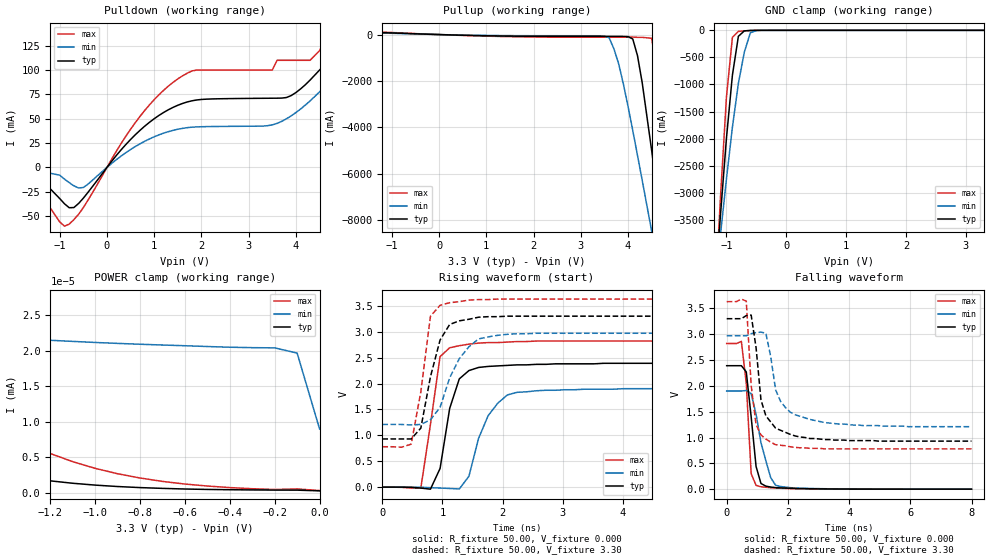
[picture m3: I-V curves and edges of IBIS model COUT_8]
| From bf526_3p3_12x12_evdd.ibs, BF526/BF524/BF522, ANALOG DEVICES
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|   Model prw0408swcdg_25
[Model]   COUT_8
Model_type   I/O
Polarity   Non-Inverting
Enable   Active-Low
Vinl =   0.40V
Vinh =   2.40V
Vmeas =   1.20V
Cref =  50.00pF
Rref =   1.00M
Vref =  0.000V
C_comp   4.77pF   4.29pF   5.25pF
[Temperature Range]   25.00   0.12k   -40.00
[Voltage Range]   3.30V   2.97V   3.63V
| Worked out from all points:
|   slope of the pulldown table from 0 to 0.495 V, typ, clamps not added: 17.4 ohm
|   slope of the pullup table from 0 to 0.495 V, typ, clamps not added: 17.2 ohm
|   GND clamp passes 1 mA (typ) near -0.53 V on its own axis
|   POWER clamp passes 1 mA (typ) near -3.01 V on its own axis
|   rising waveform, R_fixture 50.00, V_fixture 0.000: 20-80 % time 254ps typ, 376ps min, 212ps max; typ from 0 V to 2.39 V
|   rising waveform, R_fixture 50.00, V_fixture 3.30: 20-80 % time 274ps typ, 410ps min, 211ps max; typ from 0.93 V to 3.3 V
|   falling waveform, R_fixture 50.00, V_fixture 0.000: 20-80 % time 248ps typ, 430ps min, 177ps max; typ from 2.39 V to 0 V
|   falling waveform, R_fixture 50.00, V_fixture 3.30: 20-80 % time 363ps typ, 532ps min, 242ps max; typ from 3.3 V to 0.93 V
[Pulldown]
| voltage   I(typ)   I(min)   I(max)
-3.3V     0A         0A         0A
-1.7V     0A         0A         -10mA
-900mV    -37.3mA    -12mA      -60.3mA
-500mV    -31.56mA   -20.64mA   -41.25mA
700mV     38.11mA    24.26mA    52.44mA
1.7V      67.22mA    40.81mA    96.76mA
3.9V      73.78mA    52.99mA    110mA
4.3V      89.73mA    68.32mA    110mA
5.1V      140mA      110mA      170mA
5.5V      170mA      59.23mA    210mA
6.1V      130mA      60.45mA    270mA
6.6V      890mA      68.62mA    3.72A
[Pullup]
| voltage   I(typ)   I(min)   I(max)
-3.3V     29.2mA     8.62mA     61mA
-2.5V     150mA      14.34mA    190mA
3.6V      -78.87mA   -140mA     -110mA
3.8V      -79.53mA   -1.25A     -110mA
4.1V      -190mA     -4.14A     -110mA
4.2V      -910mA     -5.21A     -120mA
4.3V      -2.08A     -6.29A     -120mA
4.5V      -5A        -8.48A     -160mA
4.7V      -8.09A     -10.68A    -2.62A
4.9V      -11.24A    -12.9A     -6.81A
5.1V      -14.4A     -15.12A    -11.2A
6.6V      -38.32A    -31.88A    -44.78A
[GND_clamp]
| voltage   I(typ)   I(min)   I(max)
-3.3V     -38.23A    -28.13A    -52.07A
-1.2V     -4.92A     -4.84A     -5.19A
-1.1V     -3.42A     -3.78A     -3.1A
-1V       -2A        -2.75A     -1.24A
-900mV    -830mA     -1.79A     -130mA
-800mV    -110mA     -980mA     -19.35mA
-700mV    -10.17mA   -400mA     -9.85mA
-600mV    -2.61mA    -45.18mA   -3.52mA
-500mV    -460uA     -4.57mA    -550uA
3.3V      270pA      20.45nA    210pA
[POWER_clamp]
| voltage   I(typ)   I(min)   I(max)
-3.3V     770mA      230nA      7.85A
-2.6V     27.1nA     32.41nA    9.27mA
-2.3V     16.42nA    27.61nA    47.25nA
-2V       9.44nA     24.65nA    26.73nA
-1.7V     5.12nA     22.9nA     15.66nA
-1.5V     3.3nA      22.17nA    10.58nA
-1.3V     2.1nA      21.67nA    6.92nA
-1.1V     1.34nA     21.32nA    4.38nA
-800mV    730pA      20.92nA    2.08nA
-200mV    380pA      20.41nA    460pA
-100mV    370pA      19.67nA    540pA
0V        270pA      8.98nA     310pA
[Ramp]
| variable   typ   min   max
dV/dt_r   1.43/0.22n   1.14/0.32n   1.69/0.15n
dV/dt_f   1.42/0.31n   1.06/0.48n   1.71/0.20n
R_load = 50.00
[Rising Waveform]
R_fixture = 50.00
V_fixture = 0.000
V_fixture_min = 0.000
V_fixture_max = 0.000
L_fixture = 0.000H
C_fixture = 0.000F
| time   V(typ)   V(min)   V(max)
0s        0V         0V         0V
640ps     -17.92mV   -2.16mV    -17.85mV
800ps     -39.03mV   -10.67mV   1.21V
960ps     360mV      -17.53mV   2.52V
1.12ns    1.52V      -25.78mV   2.69V
1.28ns    2.09V      -34.99mV   2.73V
1.44ns    2.25V      210mV      2.76V
1.76ns    2.33V      1.38V      2.79V
2.24ns    2.36V      1.83V      2.81V
8ns       2.39V      1.9V       2.82V
[Rising Waveform]
R_fixture = 50.00
V_fixture = 3.30
V_fixture_min = 2.97
V_fixture_max = 3.63
L_fixture = 0.000H
C_fixture = 0.000F
| time   V(typ)   V(min)   V(max)
0s        930mV      1.21V      780mV
480ps     930mV      1.2V       830mV
640ps     1.14V      1.21V      1.84V
800ps     2.13V      1.3V       3.3V
960ps     2.84V      1.54V      3.51V
1.12ns    3.14V      2.11V      3.56V
1.28ns    3.21V      2.48V      3.58V
1.6ns     3.28V      2.86V      3.62V
1.76ns    3.29V      2.9V       3.62V
8ns       3.3V       2.97V      3.63V
[Falling Waveform]
R_fixture = 50.00
V_fixture = 0.000
V_fixture_min = 0.000
V_fixture_max = 0.000
L_fixture = 0.000H
C_fixture = 0.000F
| time   V(typ)   V(min)   V(max)
0s        2.39V      1.9V       2.82V
480ps     2.39V      1.9V       2.86V
640ps     2.27V      1.91V      2.05V
800ps     1.4V       1.85V      300mV
960ps     440mV      1.45V      74.04mV
1.12ns    110mV      900mV      46.09mV
1.44ns    40.99mV    220mV      28.16mV
1.6ns     29.84mV    75.56mV    21.47mV
2.72ns    7.89mV     13.37mV    4.34mV
8ns       10.85uV    120uV      15.04uV
[Falling Waveform]
R_fixture = 50.00
V_fixture = 3.30
V_fixture_min = 2.97
V_fixture_max = 3.63
L_fixture = 0.000H
C_fixture = 0.000F
| time   V(typ)   V(min)   V(max)
0s        3.3V       2.97V      3.63V
640ps     3.36V      2.97V      3.64V
800ps     3.37V      3.01V      2.01V
960ps     2.74V      3.03V      1.25V
1.12ns    1.73V      3.04V      1.05V
1.28ns    1.42V      3.02V      970mV
1.44ns    1.3V       2.56V      910mV
1.6ns     1.18V      1.92V      860mV
2.24ns    1.03V      1.44V      810mV
8ns       930mV      1.21V      780mV
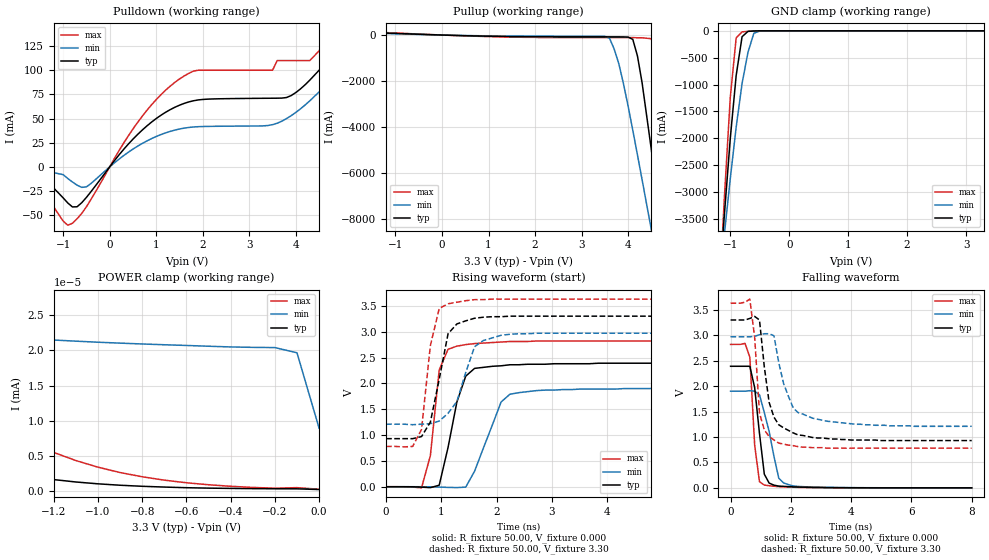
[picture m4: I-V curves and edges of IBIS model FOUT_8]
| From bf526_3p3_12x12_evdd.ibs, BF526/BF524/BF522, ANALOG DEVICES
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|   Model prw0408swcdg_3v_25
[Model]   FOUT_8
Model_type   I/O
Polarity   Non-Inverting
Enable   Active-Low
Vinl =   0.40V
Vinh =   2.40V
Vmeas =   1.20V
Cref =  50.00pF
Rref =   1.00M
Vref =  0.000V
C_comp   5.08pF   4.58pF   5.59pF
[Temperature Range]   25.00   0.12k   -40.00
[Voltage Range]   3.30V   2.97V   3.63V
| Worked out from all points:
|   slope of the pulldown table from 0 to 0.495 V, typ, clamps not added: 17.4 ohm
|   slope of the pullup table from 0 to 0.495 V, typ, clamps not added: 17.2 ohm
|   GND clamp passes 1 mA (typ) near -0.53 V on its own axis
|   POWER clamp passes 1 mA (typ) near -3.01 V on its own axis
|   rising waveform, R_fixture 50.00, V_fixture 0.000: 20-80 % time 309ps typ, 409ps min, 169ps max; typ from 0 V to 2.39 V
|   rising waveform, R_fixture 50.00, V_fixture 3.30: 20-80 % time 266ps typ, 352ps min, 210ps max; typ from 0.93 V to 3.3 V
|   falling waveform, R_fixture 50.00, V_fixture 0.000: 20-80 % time 268ps typ, 428ps min, 192ps max; typ from 2.39 V to 0 V
|   falling waveform, R_fixture 50.00, V_fixture 3.30: 20-80 % time 390ps typ, 542ps min, 240ps max; typ from 3.3 V to 0.93 V
[Pulldown]
| voltage   I(typ)   I(min)   I(max)
-3.3V     0A         0A         0A
-1.7V     0A         0A         -10mA
-900mV    -37.3mA    -12mA      -60.3mA
-500mV    -31.56mA   -20.64mA   -41.25mA
700mV     38.11mA    24.26mA    52.44mA
1.7V      67.22mA    40.81mA    96.76mA
3.9V      73.78mA    52.99mA    110mA
4.3V      89.73mA    68.32mA    110mA
5.1V      140mA      110mA      170mA
5.5V      170mA      59.23mA    210mA
6.1V      130mA      60.45mA    270mA
6.6V      890mA      68.62mA    3.72A
[Pullup]
| voltage   I(typ)   I(min)   I(max)
-3.3V     29.2mA     8.62mA     61mA
-2.5V     150mA      14.34mA    190mA
3.6V      -78.87mA   -140mA     -110mA
3.8V      -79.53mA   -1.25A     -110mA
4.1V      -190mA     -4.14A     -110mA
4.2V      -910mA     -5.21A     -120mA
4.3V      -2.08A     -6.29A     -120mA
4.5V      -5A        -8.48A     -160mA
4.7V      -8.09A     -10.68A    -2.62A
4.9V      -11.24A    -12.9A     -6.81A
5.1V      -14.4A     -15.12A    -11.2A
6.6V      -38.32A    -31.88A    -44.78A
[GND_clamp]
| voltage   I(typ)   I(min)   I(max)
-3.3V     -38.23A    -28.13A    -52.07A
-1.2V     -4.92A     -4.84A     -5.19A
-1.1V     -3.42A     -3.78A     -3.1A
-1V       -2A        -2.75A     -1.24A
-900mV    -830mA     -1.79A     -130mA
-800mV    -110mA     -980mA     -19.35mA
-700mV    -10.17mA   -400mA     -9.85mA
-600mV    -2.61mA    -45.18mA   -3.52mA
-500mV    -460uA     -4.57mA    -550uA
3.3V      270pA      20.45nA    210pA
[POWER_clamp]
| voltage   I(typ)   I(min)   I(max)
-3.3V     770mA      230nA      7.85A
-2.6V     27.1nA     32.41nA    9.27mA
-2.3V     16.42nA    27.61nA    47.25nA
-2V       9.44nA     24.65nA    26.73nA
-1.7V     5.12nA     22.9nA     15.66nA
-1.5V     3.3nA      22.17nA    10.58nA
-1.3V     2.1nA      21.67nA    6.92nA
-1.1V     1.34nA     21.32nA    4.38nA
-800mV    730pA      20.92nA    2.08nA
-200mV    380pA      20.41nA    460pA
-100mV    370pA      19.67nA    540pA
0V        270pA      8.98nA     310pA
[Ramp]
| variable   typ   min   max
dV/dt_r   1.43/0.21n   1.14/0.33n   1.69/0.16n
dV/dt_f   1.42/0.31n   1.06/0.49n   1.71/0.20n
R_load = 50.00
[Rising Waveform]
R_fixture = 50.00
V_fixture = 0.000
V_fixture_min = 0.000
V_fixture_max = 0.000
L_fixture = 0.000H
C_fixture = 0.000F
| time   V(typ)   V(min)   V(max)
0s        0V         0V         0V
640ps     -8.17mV    -460uV     -21.94mV
800ps     -17.89mV   -3.01mV    600mV
960ps     29.33mV    -7.23mV    2.26V
1.28ns    1.64V      -16.71mV   2.72V
1.44ns    2.14V      -7.59mV    2.75V
1.6ns     2.29V      300mV      2.77V
2.08ns    2.34V      1.64V      2.8V
2.24ns    2.36V      1.79V      2.81V
8ns       2.39V      1.9V       2.82V
[Rising Waveform]
R_fixture = 50.00
V_fixture = 3.30
V_fixture_min = 2.97
V_fixture_max = 3.63
L_fixture = 0.000H
C_fixture = 0.000F
| time   V(typ)   V(min)   V(max)
0s        930mV      1.21V      780mV
480ps     930mV      1.2V       780mV
640ps     970mV      1.21V      1.11V
800ps     1.25V      1.22V      2.73V
960ps     2.08V      1.27V      3.45V
1.12ns    2.96V      1.42V      3.54V
1.28ns    3.15V      1.65V      3.57V
1.6ns     3.26V      2.71V      3.62V
2.08ns    3.29V      2.93V      3.63V
8ns       3.3V       2.97V      3.63V
[Falling Waveform]
R_fixture = 50.00
V_fixture = 0.000
V_fixture_min = 0.000
V_fixture_max = 0.000
L_fixture = 0.000H
C_fixture = 0.000F
| time   V(typ)   V(min)   V(max)
0s        2.39V      1.9V       2.82V
480ps     2.39V      1.9V       2.84V
640ps     2.39V      1.91V      2.57V
800ps     1.97V      1.9V       840mV
960ps     1.07V      1.83V      120mV
1.12ns    270mV      1.48V      55.04mV
1.28ns    93.48mV    1.11V      41.63mV
1.6ns     35mV       190mV      23.4mV
1.76ns    29.42mV    96.68mV    20.12mV
8ns       2.74uV     120uV      -2.98uV
[Falling Waveform]
R_fixture = 50.00
V_fixture = 3.30
V_fixture_min = 2.97
V_fixture_max = 3.63
L_fixture = 0.000H
C_fixture = 0.000F
| time   V(typ)   V(min)   V(max)
0s        3.3V       2.97V      3.63V
640ps     3.33V      2.97V      3.71V
800ps     3.37V      2.98V      2.96V
960ps     3.3V       3.01V      1.47V
1.28ns    1.68V      3.03V      1.01V
1.44ns    1.39V      2.99V      940mV
1.6ns     1.24V      2.46V      880mV
2.08ns    1.08V      1.57V      830mV
2.72ns    990mV      1.37V      790mV
8ns       930mV      1.21V      780mV
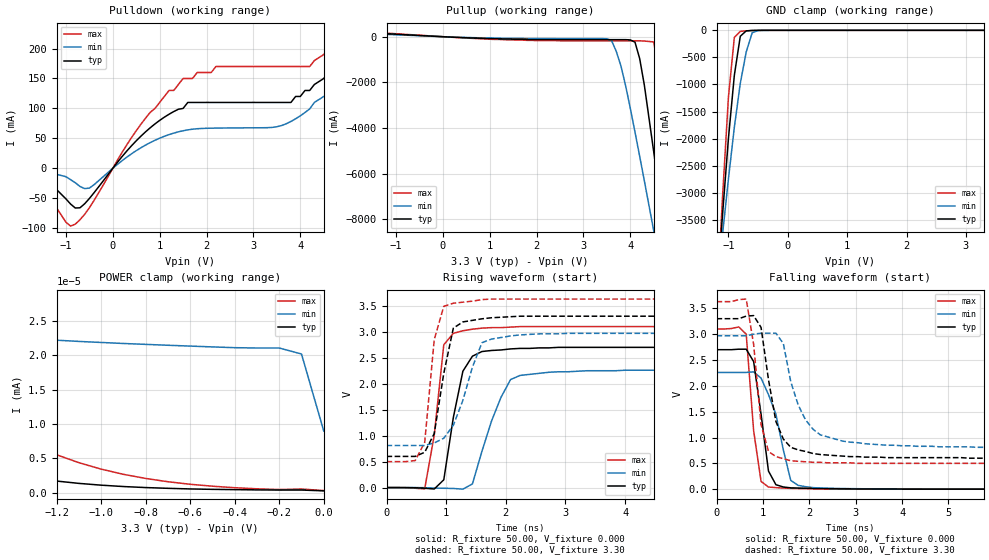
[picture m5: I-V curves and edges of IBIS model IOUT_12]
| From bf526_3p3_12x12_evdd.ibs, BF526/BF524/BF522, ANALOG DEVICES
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|   Model prw0812swcdg_25
[Model]   IOUT_12
Model_type   I/O
Polarity   Non-Inverting
Enable   Active-Low
Vinl =   0.40V
Vinh =   2.40V
Vmeas =   1.20V
Cref =  50.00pF
Rref =   1.00M
Vref =  0.000V
C_comp   4.62pF   4.16pF   5.08pF
[Temperature Range]   25.00   0.12k   -40.00
[Voltage Range]   3.30V   2.97V   3.63V
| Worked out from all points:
|   slope of the pulldown table from 0 to 0.495 V, typ, clamps not added: 10.9 ohm
|   slope of the pullup table from 0 to 0.495 V, typ, clamps not added: 10.8 ohm
|   GND clamp passes 1 mA (typ) near -0.53 V on its own axis
|   POWER clamp passes 1 mA (typ) near -3.01 V on its own axis
|   rising waveform, R_fixture 50.00, V_fixture 0.000: 20-80 % time 254ps typ, 415ps min, 195ps max; typ from 0 V to 2.7 V
|   rising waveform, R_fixture 50.00, V_fixture 3.30: 20-80 % time 249ps typ, 380ps min, 178ps max; typ from 0.6 V to 3.3 V
|   falling waveform, R_fixture 50.00, V_fixture 0.000: 20-80 % time 244ps typ, 394ps min, 199ps max; typ from 2.7 V to 0 V
|   falling waveform, R_fixture 50.00, V_fixture 3.30: 20-80 % time 341ps typ, 506ps min, 235ps max; typ from 3.3 V to 0.6 V
[Pulldown]
| voltage   I(typ)   I(min)   I(max)
-3.3V     0A         0A         0A
-2.1V     0A         0A         0A
-900mV    -59.7mA    -19mA      -96.5mA
-500mV    -50.5mA    -33.03mA   -66mA
600mV     53.68mA    34.3mA     73.6mA
1.5V      100mA      62.7mA     150mA
3.8V      110mA      78.23mA    170mA
5.1V      210mA      170mA      260mA
5.5V      260mA      93.31mA    320mA
5.9V      300mA      93.01mA    380mA
6.1V      200mA      95.25mA    410mA
6.6V      960mA      110mA      3.87A
[Pullup]
| voltage   I(typ)   I(min)   I(max)
-3.3V     42mA       12.24mA    86mA
-2.7V     200mA      16.46mA    290mA
3.6V      -130mA     -170mA     -180mA
3.8V      -130mA     -1.28A     -180mA
4.1V      -240mA     -4.18A     -180mA
4.2V      -960mA     -5.24A     -180mA
4.3V      -2.13A     -6.32A     -190mA
4.5V      -5.05A     -8.51A     -230mA
4.7V      -8.14A     -10.71A    -2.69A
4.9V      -11.28A    -12.93A    -6.88A
5.1V      -14.45A    -15.15A    -11.27A
6.6V      -38.37A    -31.91A    -44.86A
[GND_clamp]
| voltage   I(typ)   I(min)   I(max)
-3.3V     -38.23A    -28.13A    -52.07A
-1.2V     -4.92A     -4.84A     -5.19A
-1.1V     -3.42A     -3.78A     -3.1A
-1V       -2A        -2.75A     -1.24A
-900mV    -830mA     -1.79A     -130mA
-800mV    -110mA     -980mA     -19.35mA
-700mV    -10.17mA   -400mA     -9.85mA
-600mV    -2.61mA    -45.18mA   -3.52mA
-500mV    -460uA     -4.57mA    -550uA
3.3V      270pA      21.08nA    210pA
[POWER_clamp]
| voltage   I(typ)   I(min)   I(max)
-3.3V     770mA      230nA      7.85A
-2.7V     34.08nA    35.51nA    340mA
-2.6V     27.13nA    33.37nA    9.27mA
-2.4V     19.53nA    29.9nA     610nA
-2.1V     11.45nA    26.35nA    31.53nA
-2V       9.46nA     25.51nA    26.73nA
-1.6V     4.14nA     23.31nA    12.92nA
-1.3V     2.12nA     22.43nA    6.92nA
-800mV    750pA      21.61nA    2.08nA
-200mV    390pA      21.08nA    460pA
-100mV    390pA      20.21nA    540pA
0V        270pA      8.99nA     310pA
[Ramp]
| variable   typ   min   max
dV/dt_r   1.62/0.20n   1.36/0.32n   1.86/0.14n
dV/dt_f   1.62/0.27n   1.30/0.43n   1.88/0.20n
R_load = 50.00
[Rising Waveform]
R_fixture = 50.00
V_fixture = 0.000
V_fixture_min = 0.000
V_fixture_max = 0.000
L_fixture = 0.000H
C_fixture = 0.000F
| time   V(typ)   V(min)   V(max)
0s        0V         0V         0V
640ps     -12.99mV   -2.01mV    -25.12mV
800ps     -27.4mV    -9.06mV    1.01V
960ps     150mV      -13.2mV    2.75V
1.12ns    1.35V      -17.31mV   2.97V
1.28ns    2.24V      -30.54mV   3.02V
1.44ns    2.53V      70.07mV    3.05V
1.92ns    2.65V      1.74V      3.08V
2.24ns    2.68V      2.16V      3.1V
8ns       2.7V       2.26V      3.1V
[Rising Waveform]
R_fixture = 50.00
V_fixture = 3.30
V_fixture_min = 2.97
V_fixture_max = 3.63
L_fixture = 0.000H
C_fixture = 0.000F
| time   V(typ)   V(min)   V(max)
0s        600mV      810mV      500mV
480ps     600mV      810mV      520mV
640ps     680mV      810mV      870mV
800ps     1.04V      860mV      2.85V
960ps     2.2V       950mV      3.49V
1.12ns    3.07V      1.2V       3.55V
1.6ns     3.25V      2.79V      3.62V
1.76ns    3.27V      2.86V      3.63V
3.04ns    3.3V       2.97V      3.63V
8ns       3.3V       2.97V      3.63V
[Falling Waveform]
R_fixture = 50.00
V_fixture = 0.000
V_fixture_min = 0.000
V_fixture_max = 0.000
L_fixture = 0.000H
C_fixture = 0.000F
| time   V(typ)   V(min)   V(max)
0s        2.7V       2.26V      3.1V
480ps     2.71V      2.26V      3.14V
640ps     2.71V      2.26V      3V
800ps     2.47V      2.27V      1.13V
960ps     1.45V      2.15V      150mV
1.12ns    350mV      1.83V      40.93mV
1.28ns    86.15mV    1.45V      29.38mV
1.6ns     25.64mV    170mV      15.47mV
1.76ns    21.11mV    73.27mV    13.14mV
8ns       18.07uV    64.3uV     6.9uV
[Falling Waveform]
R_fixture = 50.00
V_fixture = 3.30
V_fixture_min = 2.97
V_fixture_max = 3.63
L_fixture = 0.000H
C_fixture = 0.000F
| time   V(typ)   V(min)   V(max)
0s        3.3V       2.97V      3.63V
640ps     3.35V      2.97V      3.68V
800ps     3.36V      3V         2.8V
960ps     3.13V      3.02V      1.25V
1.12ns    2.12V      3.02V      730mV
1.28ns    1.31V      3.02V      630mV
1.44ns    970mV      2.82V      590mV
1.76ns    760mV      1.63V      540mV
2.24ns    670mV      1.05V      520mV
8ns       600mV      810mV      500mV
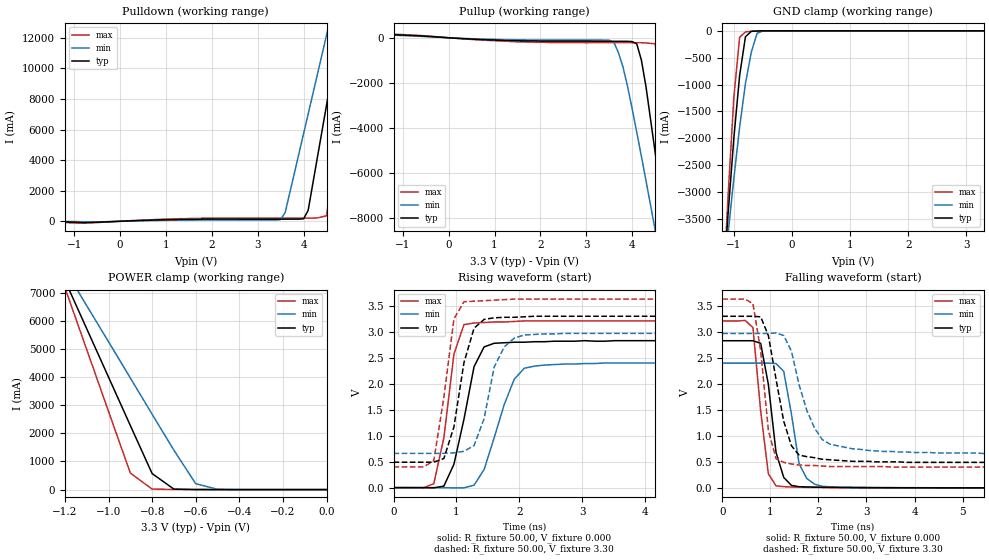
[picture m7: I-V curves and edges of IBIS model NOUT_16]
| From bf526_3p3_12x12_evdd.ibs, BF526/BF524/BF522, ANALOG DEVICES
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|   Model prw1216hcdg_25
[Model]   NOUT_16
Model_type   I/O
Polarity   Non-Inverting
Enable   Active-Low
Vinl =   0.40V
Vinh =   2.40V
Vmeas =   1.20V
Cref =  50.00pF
Rref =   1.00M
Vref =  0.000V
C_comp   4.70pF   4.23pF   5.17pF
[Temperature Range]   25.00   0.12k   -40.00
[Voltage Range]   3.30V   2.97V   3.63V
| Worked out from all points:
|   slope of the pulldown table from 0 to 0.495 V, typ, clamps not added: 8.7 ohm
|   slope of the pullup table from 0 to 0.495 V, typ, clamps not added: 8.43 ohm
|   GND clamp passes 1 mA (typ) near -0.52 V on its own axis
|   POWER clamp passes 1 mA (typ) near -0.53 V on its own axis
|   rising waveform, R_fixture 50.00, V_fixture 0.000: 20-80 % time 288ps typ, 390ps min, 217ps max; typ from 0 V to 2.83 V
|   rising waveform, R_fixture 50.00, V_fixture 3.30: 20-80 % time 270ps typ, 301ps min, 223ps max; typ from 0.49 V to 3.3 V
|   falling waveform, R_fixture 50.00, V_fixture 0.000: 20-80 % time 253ps typ, 254ps min, 220ps max; typ from 2.83 V to 0 V
|   falling waveform, R_fixture 50.00, V_fixture 3.30: 20-80 % time 361ps typ, 470ps min, 240ps max; typ from 3.3 V to 0.49 V
[Pulldown]
| voltage   I(typ)   I(min)   I(max)
-3.3V     0A         0A         -10mA
-800mV    -82.8mA    -31.1mA    -120mA
1.3V      120mA      73.45mA    170mA
3.5V      140mA      110mA      210mA
3.6V      140mA      580mA      210mA
4V        160mA      5.73A      210mA
4.1V      710mA      7.01A      210mA
4.5V      7.59A      12.17A     360mA
4.7V      11.02A     14.75A     4.54A
4.9V      14.47A     17.33A     8.94A
5.1V      17.91A     19.91A     13.34A
6.6V      44.58A     39.34A     49.85A
[Pullup]
| voltage   I(typ)   I(min)   I(max)
-3.3V     300mA      300mA      320mA
1.5V      -130mA     -92.18mA   -180mA
3.6V      -160mA     -200mA     -220mA
3.8V      -160mA     -1.3A      -220mA
4.1V      -270mA     -4.2A      -220mA
4.2V      -990mA     -5.26A     -220mA
4.3V      -2.16A     -6.34A     -230mA
4.5V      -5.08A     -8.53A     -270mA
4.7V      -8.17A     -10.73A    -2.73A
4.9V      -11.31A    -12.95A    -6.92A
5.1V      -14.48A    -15.17A    -11.31A
6.6V      -38.4A     -31.93A    -44.89A
[GND_clamp]
| voltage   I(typ)   I(min)   I(max)
-3.3V     -38.23A    -28.13A    -52.07A
-1.2V     -4.92A     -4.84A     -5.19A
-1.1V     -3.42A     -3.78A     -3.1A
-1V       -2A        -2.75A     -1.24A
-900mV    -830mA     -1.79A     -120mA
-800mV    -110mA     -980mA     -19.29mA
-700mV    -10.14mA   -400mA     -9.82mA
-600mV    -2.6mA     -45.13mA   -3.51mA
-500mV    -470uA     -4.54mA    -560uA
3.3V      250pA      110uA      -8.75uA
[POWER_clamp]
| voltage   I(typ)   I(min)   I(max)
-3.3V     44.38A     34.94A     61.27A
-1.2V     7.44A      7.83A      7.18A
-1.1V     5.72A      6.54A      4.98A
-900mV    2.28A      3.97A      590mA
-800mV    570mA      2.68A      17.01mA
-700mV    17.04mA    1.4A       7.1mA
-600mV    2.37mA     210mA      2.78mA
-500mV    470uA      11.87mA    550uA
0V        250pA      8.85nA     290pA
[Ramp]
| variable   typ   min   max
dV/dt_r   1.70/0.24n   1.44/0.33n   1.93/0.20n
dV/dt_f   1.69/0.29n   1.39/0.41n   1.94/0.21n
R_load = 50.00
[Rising Waveform]
R_fixture = 50.00
V_fixture = 0.000
V_fixture_min = 0.000
V_fixture_max = 0.000
L_fixture = 0.000H
C_fixture = 0.000F
| time   V(typ)   V(min)   V(max)
0s        0V         0V         0V
640ps     -3.92mV    -170uV     76.34mV
800ps     29.17mV    -1.52mV    960mV
960ps     450mV      -4.29mV    2.57V
1.12ns    1.32V      -3.14mV    3.14V
1.28ns    2.33V      46.2mV     3.17V
1.44ns    2.71V      350mV      3.18V
1.92ns    2.8V       2.09V      3.2V
2.08ns    2.8V       2.3V       3.21V
8ns       2.83V      2.4V       3.21V
[Rising Waveform]
R_fixture = 50.00
V_fixture = 3.30
V_fixture_min = 2.97
V_fixture_max = 3.63
L_fixture = 0.000H
C_fixture = 0.000F
| time   V(typ)   V(min)   V(max)
0s        490mV      660mV      400mV
640ps     490mV      660mV      520mV
800ps     560mV      660mV      1.74V
960ps     1.17V      670mV      3.25V
1.12ns    2.41V      700mV      3.58V
1.28ns    3.07V      810mV      3.59V
1.44ns    3.24V      1.33V      3.6V
1.6ns     3.27V      2.32V      3.61V
2.08ns    3.29V      2.94V      3.63V
8ns       3.3V       2.97V      3.63V
[Falling Waveform]
R_fixture = 50.00
V_fixture = 0.000
V_fixture_min = 0.000
V_fixture_max = 0.000
L_fixture = 0.000H
C_fixture = 0.000F
| time   V(typ)   V(min)   V(max)
0s        2.83V      2.4V       3.21V
480ps     2.83V      2.4V       3.22V
640ps     2.83V      2.4V       3.08V
800ps     2.78V      2.4V       1.48V
960ps     1.99V      2.4V       270mV
1.12ns    680mV      2.39V      38.62mV
1.28ns    200mV      2.24V      22.89mV
1.6ns     22.21mV    460mV      12.46mV
1.92ns    14.33mV    71.43mV    8.49mV
8ns       39.64uV    120uV      16.62uV
[Falling Waveform]
R_fixture = 50.00
V_fixture = 3.30
V_fixture_min = 2.97
V_fixture_max = 3.63
L_fixture = 0.000H
C_fixture = 0.000F
| time   V(typ)   V(min)   V(max)
0s        3.3V       2.97V      3.63V
640ps     3.3V       2.97V      3.54V
800ps     3.29V      2.97V      2.64V
960ps     2.93V      2.97V      1.11V
1.12ns    2.09V      2.98V      560mV
1.28ns    1.28V      2.93V      490mV
1.6ns     630mV      1.98V      440mV
1.92ns    580mV      1.15V      430mV
2.24ns    540mV      840mV      410mV
8ns       490mV      660mV      400mV
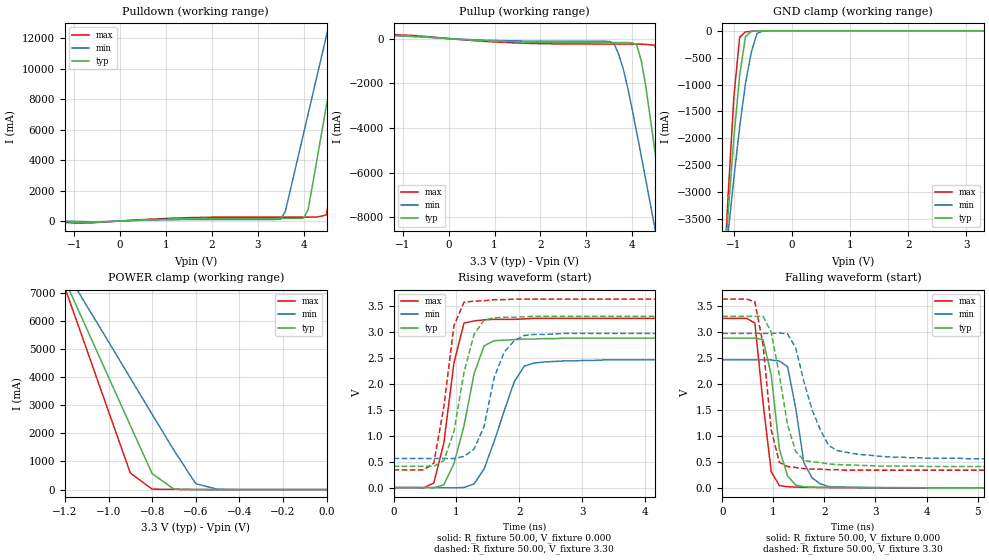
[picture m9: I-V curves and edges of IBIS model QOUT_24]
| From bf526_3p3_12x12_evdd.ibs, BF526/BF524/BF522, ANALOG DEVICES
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|   Model prw1624cdg_25
[Model]   QOUT_24
Model_type   I/O
Polarity   Non-Inverting
Enable   Active-Low
Vinl =   0.40V
Vinh =   2.40V
Vmeas =   1.20V
Cref =  50.00pF
Rref =   1.00M
Vref =  0.000V
C_comp   4.55pF   4.10pF   5.01pF
[Temperature Range]   25.00   0.12k   -40.00
[Voltage Range]   3.30V   2.97V   3.63V
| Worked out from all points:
|   slope of the pulldown table from 0 to 0.495 V, typ, clamps not added: 7.25 ohm
|   slope of the pullup table from 0 to 0.495 V, typ, clamps not added: 7.49 ohm
|   GND clamp passes 1 mA (typ) near -0.53 V on its own axis
|   POWER clamp passes 1 mA (typ) near -0.53 V on its own axis
|   rising waveform, R_fixture 50.00, V_fixture 0.000: 20-80 % time 328ps typ, 420ps min, 246ps max; typ from 0 V to 2.88 V
|   rising waveform, R_fixture 50.00, V_fixture 3.30: 20-80 % time 296ps typ, 330ps min, 227ps max; typ from 0.41 V to 3.3 V
|   falling waveform, R_fixture 50.00, V_fixture 0.000: 20-80 % time 243ps typ, 246ps min, 220ps max; typ from 2.88 V to 0 V
|   falling waveform, R_fixture 50.00, V_fixture 3.30: 20-80 % time 338ps typ, 472ps min, 232ps max; typ from 3.3 V to 0.41 V
[Pulldown]
| voltage   I(typ)   I(min)   I(max)
-3.3V     0A         0A         -10mA
-800mV    -99.3mA    -37.1mA    -140mA
1.6V      160mA      96.25mA    230mA
3.5V      170mA      130mA      250mA
3.6V      170mA      600mA      250mA
4V        190mA      5.74A      250mA
4.1V      740mA      7.03A      250mA
4.5V      7.61A      12.18A     400mA
4.7V      11.05A     14.76A     4.58A
4.9V      14.5A      17.34A     8.98A
5.1V      17.94A     19.93A     13.38A
6.6V      44.61A     39.37A     49.91A
[Pullup]
| voltage   I(typ)   I(min)   I(max)
-3.3V     340mA      340mA      360mA
1V        -120mA     -83mA      -150mA
3.6V      -180mA     -210mA     -250mA
3.8V      -180mA     -1.31A     -250mA
4.1V      -290mA     -4.21A     -250mA
4.2V      -1.01A     -5.28A     -250mA
4.3V      -2.18A     -6.36A     -260mA
4.5V      -5.1A      -8.54A     -300mA
4.7V      -8.19A     -10.75A    -2.76A
4.9V      -11.33A    -12.96A    -6.95A
5.1V      -14.5A     -15.19A    -11.34A
6.6V      -38.42A    -31.95A    -44.92A
[GND_clamp]
| voltage   I(typ)   I(min)   I(max)
-3.3V     -38.23A    -28.13A    -52.07A
-1.2V     -4.92A     -4.84A     -5.19A
-1.1V     -3.42A     -3.78A     -3.1A
-1V       -2A        -2.75A     -1.24A
-900mV    -830mA     -1.79A     -120mA
-800mV    -110mA     -980mA     -19.28mA
-700mV    -10.13mA   -400mA     -9.8mA
-600mV    -2.59mA    -45.13mA   -3.5mA
-500mV    -460uA     -4.53mA    -550uA
3.3V      250pA      100uA      190pA
[POWER_clamp]
| voltage   I(typ)   I(min)   I(max)
-3.3V     44.38A     34.94A     61.27A
-1.2V     7.44A      7.83A      7.18A
-1.1V     5.72A      6.54A      4.98A
-900mV    2.28A      3.97A      590mA
-800mV    570mA      2.68A      16.99mA
-700mV    17.03mA    1.4A       7.08mA
-600mV    2.36mA     210mA      2.77mA
-500mV    460uA      11.86mA    530uA
0V        250pA      8.84nA     290pA
[Ramp]
| variable   typ   min   max
dV/dt_r   1.73/0.27n   1.48/0.36n   1.96/0.22n
dV/dt_f   1.73/0.26n   1.45/0.39n   1.98/0.20n
R_load = 50.00
[Rising Waveform]
R_fixture = 50.00
V_fixture = 0.000
V_fixture_min = 0.000
V_fixture_max = 0.000
L_fixture = 0.000H
C_fixture = 0.000F
| time   V(typ)   V(min)   V(max)
0s        0V         0V         0V
640ps     -4.91mV    -240uV     88.24mV
800ps     54.79mV    -1.7mV     860mV
960ps     460mV      -5.48mV    2.4V
1.12ns    1.19V      1.75mV     3.17V
1.28ns    2.19V      70.39mV    3.21V
1.44ns    2.73V      360mV      3.23V
1.92ns    2.85V      2.04V      3.24V
2.24ns    2.86V      2.4V       3.26V
8ns       2.88V      2.46V      3.26V
[Rising Waveform]
R_fixture = 50.00
V_fixture = 3.30
V_fixture_min = 2.97
V_fixture_max = 3.63
L_fixture = 0.000H
C_fixture = 0.000F
| time   V(typ)   V(min)   V(max)
0s        410mV      560mV      340mV
640ps     410mV      560mV      470mV
800ps     520mV      560mV      1.56V
960ps     1.08V      560mV      3.12V
1.12ns    2.22V      600mV      3.57V
1.28ns    2.95V      740mV      3.59V
1.44ns    3.23V      1.18V      3.6V
1.76ns    3.28V      2.61V      3.62V
2.08ns    3.29V      2.93V      3.63V
8ns       3.3V       2.97V      3.63V
[Falling Waveform]
R_fixture = 50.00
V_fixture = 0.000
V_fixture_min = 0.000
V_fixture_max = 0.000
L_fixture = 0.000H
C_fixture = 0.000F
| time   V(typ)   V(min)   V(max)
0s        2.88V      2.46V      3.26V
640ps     2.88V      2.46V      3.17V
800ps     2.85V      2.46V      1.63V
960ps     2.17V      2.46V      310mV
1.12ns    740mV      2.44V      43.01mV
1.28ns    230mV      2.33V      21.66mV
1.44ns    52.95mV    1.53V      14.33mV
1.6ns     18.85mV    480mV      10.69mV
1.92ns    12.58mV    77.57mV    7.16mV
8ns       14.8uV     63.37uV    -620nV
[Falling Waveform]
R_fixture = 50.00
V_fixture = 3.30
V_fixture_min = 2.97
V_fixture_max = 3.63
L_fixture = 0.000H
C_fixture = 0.000F
| time   V(typ)   V(min)   V(max)
0s        3.3V       2.97V      3.63V
640ps     3.3V       2.97V      3.58V
800ps     3.3V       2.97V      2.75V
960ps     2.99V      2.97V      1.11V
1.12ns    2.16V      2.98V      490mV
1.28ns    1.21V      2.96V      410mV
1.6ns     530mV      2.04V      370mV
1.92ns    490mV      1.12V      360mV
2.24ns    450mV      720mV      350mV
8ns       410mV      560mV      340mV
